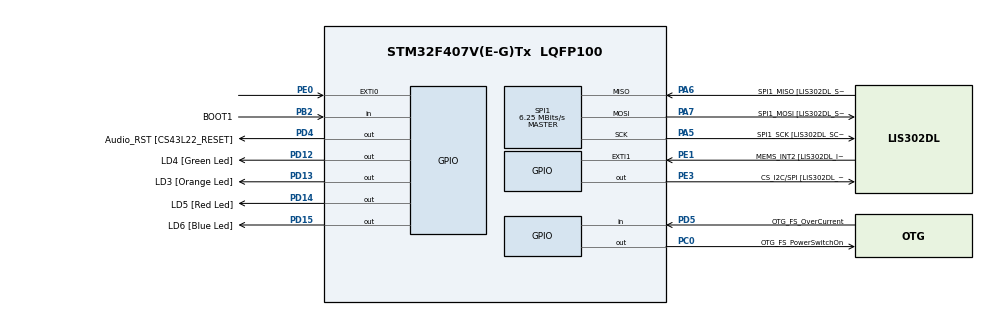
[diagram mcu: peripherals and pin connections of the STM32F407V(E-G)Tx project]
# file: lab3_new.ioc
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Mcu.Family=STM32F4
Mcu.Name=STM32F407V(E-G)Tx
Mcu.Package=LQFP100
NVIC.EXTI0_IRQn=true\:5\:0\:true\:false\:true\:true\:true
NVIC.PriorityGroup=NVIC_PRIORITYGROUP_4
NVIC.TIM7_IRQn=true\:0\:0\:false\:false\:true\:false\:true
NVIC.TimeBase=TIM7_IRQn
NVIC.TimeBaseIP=TIM7
PA10.GPIO_Label=OTG_FS_ID
PA10.GPIO_Mode=GPIO_MODE_AF_PP
PA10.GPIO_PuPd=GPIO_NOPULL
PA10.GPIO_Speed=GPIO_SPEED_FREQ_LOW
PA10.Signal=USB_OTG_FS_ID
PA11.GPIO_Label=OTG_FS_DM
PA11.GPIO_Mode=GPIO_MODE_AF_PP
PA11.GPIO_PuPd=GPIO_NOPULL
PA11.GPIO_Speed=GPIO_SPEED_FREQ_LOW
PA11.Signal=USB_OTG_FS_DM
PA12.GPIO_Label=OTG_FS_DP
PA12.GPIO_Mode=GPIO_MODE_AF_PP
PA12.GPIO_PuPd=GPIO_NOPULL
PA12.GPIO_Speed=GPIO_SPEED_FREQ_LOW
PA12.Signal=USB_OTG_FS_DP
PA13.GPIO_Label=SWDIO
PA13.Mode=Serial_Wire
PA13.Signal=SYS_JTMS-SWDIO
PA14.GPIO_Label=SWCLK
PA14.Mode=Serial_Wire
PA14.Signal=SYS_JTCK-SWCLK
PA4.GPIO_Label=I2S3_WS [CS43L22_LRCK]
PA4.GPIO_Mode=GPIO_MODE_AF_PP
PA4.GPIO_PuPd=GPIO_NOPULL
PA4.GPIO_Speed=GPIO_SPEED_FREQ_LOW
PA4.Signal=I2S3_WS
PA5.GPIO_Label=SPI1_SCK [LIS302DL_SCL/SPC]
PA5.GPIO_Mode=GPIO_MODE_AF_PP
PA5.GPIO_PuPd=GPIO_NOPULL
PA5.GPIO_Speed=GPIO_SPEED_FREQ_LOW
PA5.Mode=Full_Duplex_Master
PA5.Signal=SPI1_SCK
PA6.GPIO_Label=SPI1_MISO [LIS302DL_SDO]
PA6.GPIO_Mode=GPIO_MODE_AF_PP
PA6.GPIO_PuPd=GPIO_NOPULL
PA6.GPIO_Speed=GPIO_SPEED_FREQ_LOW
PA6.Mode=Full_Duplex_Master
PA6.Signal=SPI1_MISO
PA7.GPIO_Label=SPI1_MOSI [LIS302DL_SDA/SDI/SDO]
PA7.GPIO_Mode=GPIO_MODE_AF_PP
PA7.GPIO_PuPd=GPIO_NOPULL
PA7.GPIO_Speed=GPIO_SPEED_FREQ_LOW
PA7.Mode=Full_Duplex_Master
PA7.Signal=SPI1_MOSI
PA9.GPIO_Label=VBUS_FS
PA9.GPIO_Mode=GPIO_MODE_INPUT
PA9.GPIO_PuPd=GPIO_NOPULL
PA9.Signal=USB_OTG_FS_VBUS
PB10.GPIO_Label=CLK_IN [MP45DT02_CLK]
PB10.GPIO_Mode=GPIO_MODE_AF_PP
PB10.GPIO_PuPd=GPIO_NOPULL
PB10.GPIO_Speed=GPIO_SPEED_FREQ_LOW
PB10.Signal=I2S2_CK
PB2.GPIO_Label=BOOT1
PB2.GPIO_Mode=GPIO_MODE_INPUT
PB2.GPIO_PuPd=GPIO_NOPULL
PB2.Signal=GPIO_Input
PB3.GPIO_Label=SWO
PB3.Signal=SYS_JTDO-SWO
PB6.GPIO_Label=Audio_SCL [CS43L22_SCL]
PB6.GPIO_Mode=GPIO_MODE_AF_OD
PB6.GPIO_PuPd=GPIO_NOPULL
PB6.GPIO_Speed=GPIO_SPEED_FREQ_LOW
PB6.Signal=I2C1_SCL
PB9.GPIO_Label=Audio_SDA [CS43L22_SDA]
PB9.GPIO_Mode=GPIO_MODE_AF_OD
PB9.GPIO_PuPd=GPIO_NOPULL
PB9.GPIO_Speed=GPIO_SPEED_FREQ_LOW
PB9.Signal=I2C1_SDA
PC0.GPIO_Label=OTG_FS_PowerSwitchOn
PC0.GPIO_PuPd=GPIO_NOPULL
PC0.GPIO_Speed=GPIO_SPEED_FREQ_LOW
PC0.PinState=GPIO_PIN_SET
PC0.Signal=GPIO_Output
PC10.GPIO_Label=I2S3_SCK [CS43L22_SCLK]
PC10.GPIO_Mode=GPIO_MODE_AF_PP
PC10.GPIO_PuPd=GPIO_NOPULL
PC10.GPIO_Speed=GPIO_SPEED_FREQ_LOW
PC10.Signal=I2S3_CK
PC12.GPIO_Label=I2S3_SD [CS43L22_SDIN]
PC12.GPIO_Mode=GPIO_MODE_AF_PP
PC12.GPIO_PuPd=GPIO_NOPULL
PC12.GPIO_Speed=GPIO_SPEED_FREQ_LOW
PC12.Signal=I2S3_SD
PC14-OSC32_IN.GPIO_Label=PC14-OSC32_IN
PC14-OSC32_IN.Signal=RCC_OSC32_IN
PC15-OSC32_OUT.GPIO_Label=PC15-OSC32_OUT
PC15-OSC32_OUT.Signal=RCC_OSC32_OUT
PC3.GPIO_Label=PDM_OUT [MP45DT02_DOUT]
PC3.GPIO_Mode=GPIO_MODE_AF_PP
PC3.GPIO_PuPd=GPIO_NOPULL
PC3.GPIO_Speed=GPIO_SPEED_FREQ_LOW
PC3.Signal=I2S2_SD
PC7.GPIO_Label=I2S3_MCK [CS43L22_MCLK]
PC7.GPIO_Mode=GPIO_MODE_AF_PP
PC7.GPIO_PuPd=GPIO_NOPULL
PC7.GPIO_Speed=GPIO_SPEED_FREQ_LOW
PC7.Signal=I2S3_MCK
PD12.GPIO_Label=LD4 [Green Led]
PD12.GPIO_PuPd=GPIO_NOPULL
PD12.GPIO_Speed=GPIO_SPEED_FREQ_LOW
PD12.Signal=GPIO_Output
PD13.GPIO_Label=LD3 [Orange Led]
PD13.GPIO_PuPd=GPIO_NOPULL
PD13.GPIO_Speed=GPIO_SPEED_FREQ_LOW
PD13.Signal=GPIO_Output
PD14.GPIO_Label=LD5 [Red Led]
PD14.GPIO_PuPd=GPIO_NOPULL
PD14.GPIO_Speed=GPIO_SPEED_FREQ_LOW
PD14.Signal=GPIO_Output
PD15.GPIO_Label=LD6 [Blue Led]
PD15.GPIO_PuPd=GPIO_NOPULL
PD15.GPIO_Speed=GPIO_SPEED_FREQ_LOW
PD15.Signal=GPIO_Output
PD4.GPIO_Label=Audio_RST [CS43L22_RESET]
PD4.GPIO_PuPd=GPIO_NOPULL
PD4.GPIO_Speed=GPIO_SPEED_FREQ_LOW
PD4.Signal=GPIO_Output
PD5.GPIO_Label=OTG_FS_OverCurrent
PD5.GPIO_Mode=GPIO_MODE_INPUT
PD5.GPIO_PuPd=GPIO_NOPULL
PD5.Signal=GPIO_Input
PE0.Signal=GPXTI0
PE1.GPIO_Label=MEMS_INT2 [LIS302DL_INT2]
PE1.GPIO_ModeDefaultEXTI=GPIO_MODE_EVT_RISING
PE1.GPIO_PuPd=GPIO_NOPULL
PE1.Signal=GPXTI1
PE3.GPIO_Label=CS_I2C/SPI [LIS302DL_CS_I2C/SPI]
PE3.GPIO_PuPd=GPIO_NOPULL
PE3.GPIO_Speed=GPIO_SPEED_FREQ_LOW
PE3.Signal=GPIO_Output
PH0-OSC_IN.GPIO_Label=PH0-OSC_IN
PH0-OSC_IN.Signal=RCC_OSC_IN
PH1-OSC_OUT.GPIO_Label=PH1-OSC_OUT
PH1-OSC_OUT.Signal=RCC_OSC_OUT
ProjectManager.HeapSize=0x200
ProjectManager.StackSize=0x400
ProjectManager.TargetToolchain=STM32CubeIDE
RCC.48MHZClocksFreq_Value=14285714.285714285
RCC.AHBFreq_Value=25000000
RCC.APB1CLKDivider=RCC_HCLK_DIV4
RCC.APB1Freq_Value=6250000
RCC.APB1TimFreq_Value=12500000
RCC.APB2CLKDivider=RCC_HCLK_DIV2
RCC.APB2Freq_Value=12500000
RCC.APB2TimFreq_Value=25000000
RCC.CortexFreq_Value=25000000
RCC.HCLKFreq_Value=25000000
RCC.HSE_VALUE=8000000
RCC.HSI_VALUE=16000000
RCC.LSE_VALUE=32768
RCC.PLLM=8
RCC.PLLN=50
RCC.PLLP=RCC_PLLP_DIV4
RCC.PLLQ=7
RCC.SYSCLKFreq_VALUE=25000000
RCC.SYSCLKSource=RCC_SYSCLKSOURCE_PLLCLK
RCC.VCOOutputFreq_Value=100000000
SPI1.CalculateBaudRate=6.25 MBits/s
SPI1.Direction=SPI_DIRECTION_2LINES
SPI1.Mode=SPI_MODE_MASTER
SPI1.VirtualType=VM_MASTER
VP_SYS_VS_tim7.Mode=TIM7
board=STM32F407G-DISC1

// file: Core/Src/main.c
/* USER CODE BEGIN Header */
/**
  ******************************************************************************
  * @file           : main.c
  * @brief          : Main program body
  ******************************************************************************
  * @attention
  *
  * <h2><center>&copy; Copyright (c) 2021 STMicroelectronics.
  * All rights reserved.</center></h2>
  *
  * This software component is licensed by ST under BSD 3-Clause license,
  * the "License"; You may not use this file except in compliance with the
  * License. You may obtain a copy of the License at:
  *                        opensource.org/licenses/BSD-3-Clause
  *
  ******************************************************************************
  */
/* USER CODE END Header */
#include "main.h"

/* USER CODE BEGIN Includes */
#include "FreeRTOS.h"
#include "task.h"
#include "semphr.h"

/* USER CODE END Includes */

/* USER CODE BEGIN PM */
#define LIS3DSH_WHO_AM_I_ADDR                0x0F
#define LIS3DSH_STAT_ADDR                    0x18
#define LIS3DSH_CTRL_REG4_ADDR               0x20
#define LIS3DSH_CTRL_REG1_ADDR               0x21
#define LIS3DSH_CTRL_REG2_ADDR               0x22
#define LIS3DSH_CTRL_REG3_ADDR               0x23
#define LIS3DSH_CTRL_REG5_ADDR               0x24
#define LIS3DSH_CTRL_REG6_ADDR               0x25

#define LIS3DSH_STATUS_ADDR                  0x27

#define LIS3DSH_OUT_X_L_ADDR                 0x28
#define LIS3DSH_OUT_X_H_ADDR                 0x29
#define LIS3DSH_OUT_Y_L_ADDR                 0x2A
#define LIS3DSH_OUT_Y_H_ADDR                 0x2B
#define LIS3DSH_OUT_Z_L_ADDR                 0x2C
#define LIS3DSH_OUT_Z_H_ADDR                 0x2D

#define LIS3DSH_ST1_1_ADDR                   0x40
#define LIS3DSH_ST1_2_ADDR                   0x41
#define LIS3DSH_THRS1_1_ADDR                 0x57
#define LIS3DSH_MASK1_B_ADDR                 0x59
#define LIS3DSH_MASK1_A_ADDR                 0x5A
#define LIS3DSH_SETT1_ADDR                   0x5B
#define LIS3DSH_OUTS1_ADDR                   0x5F
/* USER CODE END PM */

SPI_HandleTypeDef hspi1;

/* USER CODE BEGIN PV */

uint8_t data;
/* USER CODE END PV */

void SystemClock_Config(void);
static void MX_GPIO_Init(void);
static void MX_SPI1_Init(void);

/* USER CODE BEGIN 0 */
void MEMS_Write(uint8_t address,uint8_t data){
	HAL_GPIO_WritePin(GPIOE, GPIO_PIN_3, GPIO_PIN_RESET);
	HAL_SPI_Transmit(&hspi1,&address,1,10);
	HAL_SPI_Transmit(&hspi1,&data,1,10);
	HAL_GPIO_WritePin(GPIOE, GPIO_PIN_3,GPIO_PIN_SET);
}
void MEMS_Read(uint8_t address,uint8_t *data){
    address |= 0x80;
	HAL_GPIO_WritePin(GPIOE,GPIO_PIN_3,GPIO_PIN_RESET);
	HAL_SPI_Transmit(&hspi1,&address,1,10);
	HAL_SPI_Receive(&hspi1,data,1,10);
	HAL_GPIO_WritePin(GPIOE,GPIO_PIN_3,GPIO_PIN_SET);
}
void Green_LED_Task(void *pvParameters)
{
	for(;;)
	{
		//綠燈閃爍
		uint8_t data;
		MEMS_Read(LIS3DSH_WHO_AM_I_ADDR,&data);
		if(data == 0x3F){
			HAL_GPIO_TogglePin(GPIOD, GPIO_PIN_12);
		}
		vTaskDelay(500/portTICK_RATE_MS);
	}
}
SemaphoreHandle_t xSemaphore;
void vHandlerTask( void *pvParameters )
{
	uint8_t data;
	for(;;)
		{
			/* Take the semaphore */
			xSemaphoreTake( xSemaphore, portMAX_DELAY);

			// semaphore was obtained
			for(int i = 0 ; i < 10 ; i ++ ){
				uint32_t From_begin_time = HAL_GetTick();
				HAL_GPIO_TogglePin(GPIOD, GPIO_PIN_13);
				while(HAL_GetTick() - From_begin_time < 250/portTICK_RATE_MS){
					;
				}
			}

                // 橘燈閃5次

			// reset interrupt register

			MEMS_Read(0x5F,&data);

		}
}
void HAL_GPIO_EXTI_Callback(uint16_t GPIO_Pin)
{
	BaseType_t xHigherPriorityTaskWoken ;
	/* 紅燈 toggle */

	HAL_GPIO_TogglePin(GPIOD, GPIO_PIN_14);
	/* Give the semaphore to unblock the handler task */
	xHigherPriorityTaskWoken = pdFALSE ;
	xSemaphoreGiveFromISR( xSemaphore , &xHigherPriorityTaskWoken);
	portYIELD_FROM_ISR(xHigherPriorityTaskWoken);
}
/* USER CODE END 0 */

int main(void)
{

  /* MCU Configuration--------------------------------------------------------*/

  /* Reset of all peripherals, Initializes the Flash interface and the Systick. */
  HAL_Init();

  /* Configure the system clock */
  SystemClock_Config();

  /* Initialize all configured peripherals */
  MX_GPIO_Init();
  MX_SPI1_Init();
  /* USER CODE BEGIN 2 */
  // 寫入 register //
  MEMS_Write(0x21,0x01);
  MEMS_Write(0x23,0x48);
  MEMS_Write(0x20,0x67);
  MEMS_Write(0x24,0x00);
  MEMS_Write(0x57,0x55);
  MEMS_Write(0x40,0x05);
  MEMS_Write(0x41,0x11);
  MEMS_Write(0x59,0xFC);
  MEMS_Write(0x5A,0xFC);
  MEMS_Write(0x5B,0x1);

  // Create the semaphore //
  xSemaphore = xSemaphoreCreateBinary();

  // task create //
  xTaskCreate(
		  	  Green_LED_Task,
      		  "Green_LED_Task",
      		  128,
      		  NULL,
      		  1,
      		  NULL);
  xTaskCreate(
		  	  vHandlerTask,
        		  "vHandlerTask",
        		  128,
        		  NULL,
        		  5,
        		  NULL);
  vTaskStartScheduler();

  // USER CODE END 2 //

  /* Infinite loop */
  while (1)
  {

  }
}

void SystemClock_Config(void)
{
  RCC_OscInitTypeDef RCC_OscInitStruct = {0};
  RCC_ClkInitTypeDef RCC_ClkInitStruct = {0};

  /** Configure the main internal regulator output voltage
  */
  __HAL_RCC_PWR_CLK_ENABLE();
  __HAL_PWR_VOLTAGESCALING_CONFIG(PWR_REGULATOR_VOLTAGE_SCALE1);
  /** Initializes the RCC Oscillators according to the specified parameters
  * in the RCC_OscInitTypeDef structure.
  */
  RCC_OscInitStruct.OscillatorType = RCC_OSCILLATORTYPE_HSI;
  RCC_OscInitStruct.HSIState = RCC_HSI_ON;
  RCC_OscInitStruct.HSICalibrationValue = RCC_HSICALIBRATION_DEFAULT;
  RCC_OscInitStruct.PLL.PLLState = RCC_PLL_NONE;
  if (HAL_RCC_OscConfig(&RCC_OscInitStruct) != HAL_OK)
  {
    Error_Handler();
  }
  /** Initializes the CPU, AHB and APB buses clocks
  */
  RCC_ClkInitStruct.ClockType = RCC_CLOCKTYPE_HCLK|RCC_CLOCKTYPE_SYSCLK
                              |RCC_CLOCKTYPE_PCLK1|RCC_CLOCKTYPE_PCLK2;
  RCC_ClkInitStruct.SYSCLKSource = RCC_SYSCLKSOURCE_HSI;
  RCC_ClkInitStruct.AHBCLKDivider = RCC_SYSCLK_DIV1;
  RCC_ClkInitStruct.APB1CLKDivider = RCC_HCLK_DIV1;
  RCC_ClkInitStruct.APB2CLKDivider = RCC_HCLK_DIV1;

  if (HAL_RCC_ClockConfig(&RCC_ClkInitStruct, FLASH_LATENCY_0) != HAL_OK)
  {
    Error_Handler();
  }
}

static void MX_SPI1_Init(void)
{

  /* SPI1 parameter configuration*/
  hspi1.Instance = SPI1;
  hspi1.Init.Mode = SPI_MODE_MASTER;
  hspi1.Init.Direction = SPI_DIRECTION_2LINES;
  hspi1.Init.DataSize = SPI_DATASIZE_8BIT;
  hspi1.Init.CLKPolarity = SPI_POLARITY_LOW;
  hspi1.Init.CLKPhase = SPI_PHASE_1EDGE;
  hspi1.Init.NSS = SPI_NSS_SOFT;
  hspi1.Init.BaudRatePrescaler = SPI_BAUDRATEPRESCALER_2;
  hspi1.Init.FirstBit = SPI_FIRSTBIT_MSB;
  hspi1.Init.TIMode = SPI_TIMODE_DISABLE;
  hspi1.Init.CRCCalculation = SPI_CRCCALCULATION_DISABLE;
  hspi1.Init.CRCPolynomial = 10;
  if (HAL_SPI_Init(&hspi1) != HAL_OK)
  {
    Error_Handler();
  }

}

static void MX_GPIO_Init(void)
{
  GPIO_InitTypeDef GPIO_InitStruct = {0};

  /* GPIO Ports Clock Enable */
  __HAL_RCC_GPIOE_CLK_ENABLE();
  __HAL_RCC_GPIOA_CLK_ENABLE();
  __HAL_RCC_GPIOD_CLK_ENABLE();

  /*Configure GPIO pin Output Level */
  HAL_GPIO_WritePin(GPIOE, GPIO_PIN_3, GPIO_PIN_RESET);

  /*Configure GPIO pin Output Level */
  HAL_GPIO_WritePin(GPIOD, GPIO_PIN_12|GPIO_PIN_13|GPIO_PIN_14, GPIO_PIN_RESET);

  /*Configure GPIO pin : PE3 */
  GPIO_InitStruct.Pin = GPIO_PIN_3;
  GPIO_InitStruct.Mode = GPIO_MODE_OUTPUT_PP;
  GPIO_InitStruct.Pull = GPIO_NOPULL;
  GPIO_InitStruct.Speed = GPIO_SPEED_FREQ_LOW;
  HAL_GPIO_Init(GPIOE, &GPIO_InitStruct);

  /*Configure GPIO pins : PD12 PD13 PD14 */
  GPIO_InitStruct.Pin = GPIO_PIN_12|GPIO_PIN_13|GPIO_PIN_14;
  GPIO_InitStruct.Mode = GPIO_MODE_OUTPUT_PP;
  GPIO_InitStruct.Pull = GPIO_NOPULL;
  GPIO_InitStruct.Speed = GPIO_SPEED_FREQ_LOW;
  HAL_GPIO_Init(GPIOD, &GPIO_InitStruct);

  /*Configure GPIO pin : PE0 */
  GPIO_InitStruct.Pin = GPIO_PIN_0;
  GPIO_InitStruct.Mode = GPIO_MODE_IT_RISING;
  GPIO_InitStruct.Pull = GPIO_NOPULL;
  HAL_GPIO_Init(GPIOE, &GPIO_InitStruct);

  /* EXTI interrupt init*/
  HAL_NVIC_SetPriority(EXTI0_IRQn, 5, 0);
  HAL_NVIC_EnableIRQ(EXTI0_IRQn);

}

void HAL_TIM_PeriodElapsedCallback(TIM_HandleTypeDef *htim)
{
  if (htim->Instance == TIM7) {
    HAL_IncTick();
  }
}

void Error_Handler(void)
{
  __disable_irq();
  while (1)
  {
  }
}
